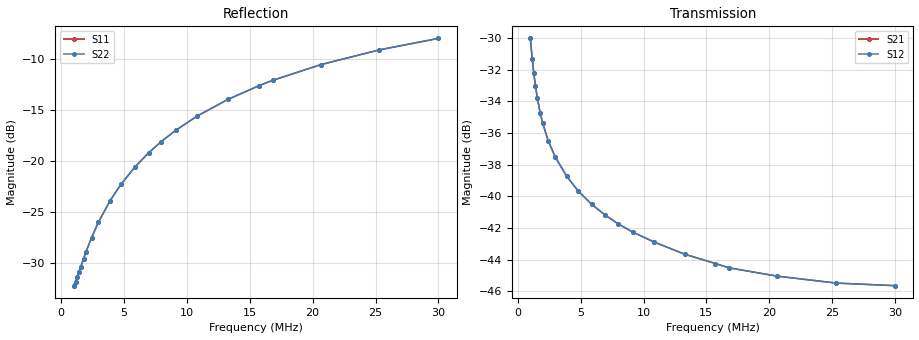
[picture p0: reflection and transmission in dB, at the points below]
! ListType=Log
!!FT240-43 10T #18 Balun
# MHZ S MA R 50
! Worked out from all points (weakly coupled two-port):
!   101 points, 1 MHz to 30 MHz, reference 50 ohm
!   highest |S21| = -30.02 dB at 1 MHz (marker M1); lowest = -45.6 dB at 30 MHz (marker M2)
!   lowest |S11| = -32.2 dB at 1 MHz (marker M3), VSWR 1.05, Z = 49.7 + j2.42 ohm
!   |S11| at or under -10 dB: start of sweep to 22.25 MHz
!   |S22| runs from -32.2 to -8.0 dB; largest |S21 - S12| = 1.9e-05
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1  0.02448 95.8  0.03155 -76.5  0.03154 -76.5  0.02446 95.8
1.145737  0.02563 94.9  0.02725 -74.3  0.02724 -74.3  0.02563 94.9
1.268816  0.02687 94.4  0.02458 -72.3  0.02457 -72.3  0.02684 94.4
1.405116  0.0284 93.6  0.02234 -70.0  0.02233 -70.0  0.02839 93.7
1.556058  0.03021 93.1  0.02045 -67.6  0.02044 -67.6  0.03022 93.1
1.782833  0.03317 92.2  0.01837 -64.3  0.01836 -64.2  0.03319 92.2
1.97435  0.03581 91.4  0.01707 -61.8  0.01706 -61.8  0.0358 91.4
2.421316  0.04208 89.9  0.01498 -57.1  0.01497 -57.1  0.04209 89.9
2.969469  0.05013 88.2  0.01334 -53.0  0.01333 -53.0  0.05019 88.2
3.89806  0.06398 86.0  0.01156 -48.3  0.01156 -48.3  0.06395 85.9
4.780527  0.0772 84.1  0.01043 -45.0  0.01042 -45.0  0.07716 84.1
5.862773  0.09338 82.1  0.009447 -41.8  0.009442 -41.8  0.09336 82.1
6.949589  0.1096 80.3  0.008728 -39.1  0.00872 -39.1  0.1096 80.3
7.9624  0.1246 78.7  0.008197 -36.9  0.008194 -36.9  0.1245 78.7
9.122814  0.1416 76.9  0.007717 -34.6  0.007715 -34.6  0.1416 76.9
10.81396  0.1661 74.4  0.007183 -31.7  0.007178 -31.7  0.1661 74.4
13.2621  0.2006 70.8  0.006568 -28.0  0.006565 -28.0  0.2006 70.8
15.72057  0.2341 67.4  0.006132 -24.4  0.006134 -24.3  0.2341 67.4
16.82715  0.2488 65.9  0.005941 -22.4  0.005942 -22.4  0.2488 65.9
20.63659  0.297 60.8  0.005596 -16.8  0.005595 -16.8  0.297 60.8
25.30843  0.3511 54.8  0.005321 -10.6  0.005322 -10.6  0.3511 54.8
30  0.3998 49.0  0.005221 -4.8  0.005221 -4.8  0.3998 49.0
